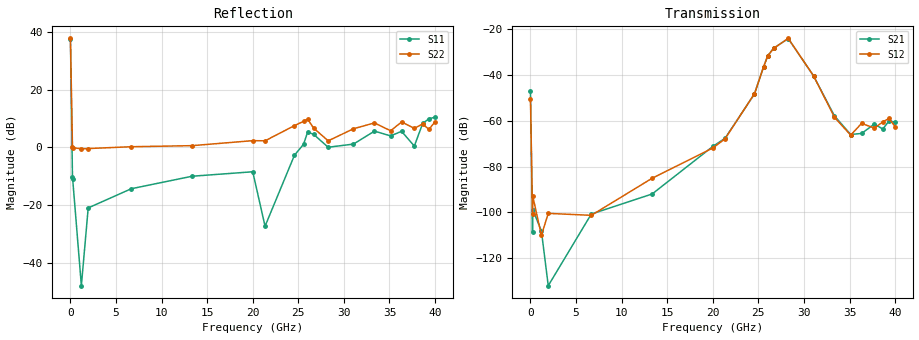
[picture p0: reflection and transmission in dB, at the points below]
!Agilent Technologies,N5230A,US43500312,A.07.50.67
!Agilent N5230A: A.07.50.67
!Date: Wednesday, December 30, 2015 19:54:21
!Correction: S11(Full 2 Port(1,2))
!S21(Full 2 Port(1,2))
!S12(Full 2 Port(1,2))
!S22(Full 2 Port(1,2))
!S2P File: Measurements: S11, S21, S12, S22:
# Hz S  dB  R 50
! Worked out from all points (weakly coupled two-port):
!   1601 points, 10 MHz to 40 GHz, reference 50 ohm
!   highest |S21| = -24.15 dB at 28.28 GHz (marker M1); lowest = -132.0 dB at 1.96 GHz (marker M2)
!   lowest |S11| = -47.7 dB at 1.21 GHz (marker M3), VSWR 1.01, Z = 50.4 + j0.207 ohm
!   |S11| at or under -10 dB: 223.7 MHz to 10.12 GHz (9.896 GHz wide, 191 % of centre); 11.17 GHz to 13.34 GHz (2.173 GHz wide, 17.7 % of centre); 14.66 GHz to 18.59 GHz (3.927 GHz wide, 23.6 % of centre) (the widest 3 of 6)
!   |S22| runs from -0.5 to 37.7 dB; largest |S21 - S12| = 0.0069
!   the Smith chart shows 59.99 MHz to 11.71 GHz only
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1e7  37.63 -146.8  -46.97 53.2  -50.36 -173.1  37.69 -147.8
2.349438e8  -10.31 -80.9  -108.57 75.3  -100.68 -120.1  0.04 -161.2
2.599375e8  -11.00 -79.9  -98.79 -176.4  -92.91 -20.7  -0.07 -162.2
1.2097e9  -47.74 30.1  -108.15 113.0  -110.07 -121.5  -0.44 -162.0
1.959512e9  -20.88 104.9  -132.02 -130.3  -100.46 97.0  -0.37 -153.7
6.683331e9  -14.25 121.0  -100.75 -162.7  -101.31 159.9  0.26 -89.1
1.335666e10  -9.93 -3.9  -91.99 -9.0  -85.12 -42.5  0.63 6.0
2.0005e10  -8.39 74.5  -71.25 93.3  -71.94 87.0  2.36 86.1
2.135466e10  -27.20 176.6  -67.65 91.3  -67.88 96.0  2.30 118.1
2.457886e10  -2.68 -96.4  -48.34 164.0  -48.20 164.8  7.55 -150.7
2.557861e10  1.11 -13.5  -36.45 139.1  -36.46 139.3  9.03 -142.0
2.602849e10  5.35 -29.1  -31.72 107.7  -31.69 107.6  9.76 -157.4
2.667833e10  4.53 -38.9  -28.36 66.8  -28.46 66.5  6.71 -175.1
2.827793e10  0.08 -7.1  -24.15 -41.0  -24.07 -41.4  2.29 171.3
3.105224e10  1.17 -80.1  -40.45 172.1  -40.39 171.0  6.47 -122.4
3.335166e10  5.64 -47.8  -57.91 168.5  -58.52 162.8  8.48 -74.7
3.512622e10  4.01 12.1  -66.03 -130.2  -66.30 -122.5  5.78 0.9
3.632592e10  5.58 56.0  -65.57 -80.6  -61.19 -78.9  8.81 60.0
3.772557e10  0.49 -135.6  -61.47 -80.6  -63.23 -91.7  6.61 126.4
3.865034e10  8.35 -96.6  -63.64 -64.6  -60.54 -63.7  8.14 155.0
3.932517e10  9.90 -71.5  -60.18 -66.2  -59.01 -71.2  6.24 100.6
4e10  10.47 -37.8  -60.55 -104.6  -62.60 -85.5  8.91 25.3
